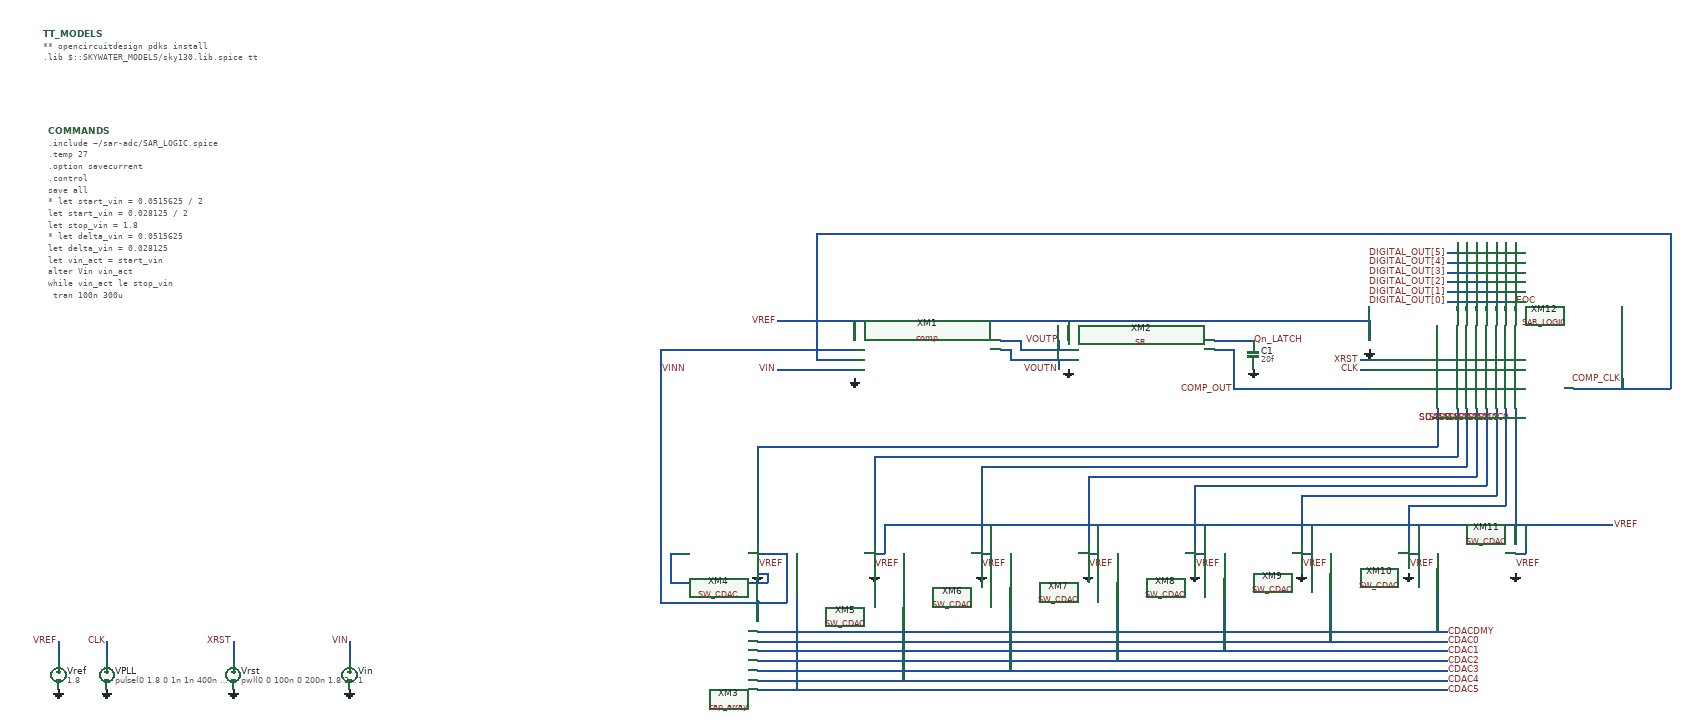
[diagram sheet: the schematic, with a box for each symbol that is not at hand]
v {xschem version=3.4.8RC file_version=1.3}
G {}
K {}
V {}
S {}
F {}
E {}
N 60 -300 60 -260 {
lab=VREF}
N 2480 -820 2760 -820 {
lab=COMP_OUT}
N 160 -300 160 -260 {
lab=CLK}
N 2740 -860 2760 -860 {
lab=CLK}
N 2740 -880 2760 -880 {
lab=XRST}
N 420 -300 420 -260 {
lab=XRST}
N 3060 -780 3060 -690 {
lab=SDAC0}
N 3050 -760 3060 -760 {
lab=SDAC0}
N 3040 -780 3040 -690 {
lab=SDAC1}
N 3030 -760 3040 -760 {
lab=SDAC1}
N 3020 -780 3020 -690 {
lab=SDAC2}
N 3010 -760 3020 -760 {
lab=SDAC2}
N 3000 -780 3000 -690 {
lab=SDAC3}
N 2990 -760 3000 -760 {
lab=SDAC3}
N 2980 -780 2980 -690 {
lab=SDAC4}
N 2970 -760 2980 -760 {
lab=SDAC4}
N 2960 -780 2960 -690 {
lab=SDAC5}
N 2950 -760 2960 -760 {
lab=SDAC5}
N 2940 -780 2940 -690 {
lab=SDAC6}
N 2930 -760 2940 -760 {
lab=SDAC6}
N 2900 -780 2900 -700 {
lab=SC}
N 2890 -760 2900 -760 {
lab=SC}
N 3180 -820 3380 -820 {
lab=COMP_CLK}
N 3280 -840 3280 -820 {
lab=COMP_CLK}
N 2000 -920 2040 -920 {
lab=VOUTP}
N 2000 -900 2020 -900 {
lab=VOUTN}
N 1500 -320 2920 -320 {
lab=CDACDMY}
N 1500 -300 2920 -300 {
lab=CDAC0}
N 1500 -280 2920 -280 {
lab=CDAC1}
N 1500 -260 2920 -260 {
lab=CDAC2}
N 1500 -240 2920 -240 {
lab=CDAC3}
N 1500 -220 2920 -220 {
lab=CDAC4}
N 1500 -200 2920 -200 {
lab=CDAC5}
N 1740 -680 2940 -680 {
lab=SDAC6}
N 1740 -680 1740 -500 {
lab=SDAC6}
N 1960 -660 1960 -500 {
lab=SDAC5}
N 1960 -660 2960 -660 {
lab=SDAC5}
N 2180 -640 2980 -640 {
lab=SDAC4}
N 2180 -640 2180 -500 {
lab=SDAC4}
N 2400 -620 2400 -500 {
lab=SDAC3}
N 2400 -620 3000 -620 {
lab=SDAC3}
N 2620 -600 3020 -600 {
lab=SDAC2}
N 2620 -600 2620 -500 {
lab=SDAC2}
N 2840 -580 2840 -500 {
lab=SDAC1}
N 3060 -690 3060 -500 {
lab=SDAC0}
N 1500 -700 2900 -700 {
lab=SC}
N 1500 -700 1500 -500 {
lab=SC}
N 1320 -480 1340 -480 {
lab=GND}
N 1320 -480 1320 -420 {
lab=GND}
N 1320 -420 1520 -420 {
lab=GND}
N 1520 -440 1520 -420 {
lab=GND}
N 1500 -440 1520 -440 {
lab=GND}
N 1500 -380 1500 -340 {
lab=VINN}
N 1300 -380 1500 -380 {
lab=VINN}
N 1300 -900 1300 -380 {
lab=VINN}
N 1300 -900 1700 -900 {
lab=VINN}
N 1500 -480 1560 -480 {
lab=VINN}
N 1560 -480 1560 -380 {
lab=VINN}
N 1500 -380 1560 -380 {
lab=VINN}
N 2840 -580 3040 -580 {
lab=SDAC1}
N 1620 -880 1700 -880 {
lab=COMP_CLK}
N 1620 -1140 1620 -880 {
lab=COMP_CLK}
N 1620 -1140 3380 -1140 {
lab=COMP_CLK}
N 3380 -1140 3380 -820 {
lab=COMP_CLK}
N 2440 -900 2480 -900 {
lab=COMP_OUT}
N 2480 -900 2480 -820 {
lab=COMP_OUT}
N 2440 -920 2520 -920 {
lab=Qn_LATCH}
N 1760 -540 3260 -540 {
lab=VREF}
N 1740 -480 1760 -480 {
lab=VREF}
N 1760 -540 1760 -480 {
lab=VREF}
N 1960 -480 1980 -480 {
lab=VREF}
N 1980 -540 1980 -480 {
lab=VREF}
N 2180 -480 2200 -480 {
lab=VREF}
N 2200 -540 2200 -480 {
lab=VREF}
N 2400 -480 2420 -480 {
lab=VREF}
N 2420 -540 2420 -480 {
lab=VREF}
N 2620 -480 2640 -480 {
lab=VREF}
N 2640 -540 2640 -480 {
lab=VREF}
N 2840 -480 2860 -480 {
lab=VREF}
N 2860 -540 2860 -480 {
lab=VREF}
N 3060 -480 3080 -480 {
lab=VREF}
N 3080 -540 3080 -480 {
lab=VREF}
N 660 -300 660 -260 {
lab=VIN}
N 1540 -860 1700 -860 {
lab=VIN}
N 2120 -880 2120 -860 {
lab=VOUTN}
N 2120 -920 2120 -900 {
lab=VOUTP}
N 2040 -920 2040 -900 {
lab=VOUTP}
N 2940 -690 2940 -680 {
lab=SDAC6}
N 2960 -690 2960 -660 {
lab=SDAC5}
N 2980 -690 2980 -640 {
lab=SDAC4}
N 3000 -690 3000 -620 {
lab=SDAC3}
N 3020 -690 3020 -600 {
lab=SDAC2}
N 3040 -690 3040 -580 {
lab=SDAC1}
N 2020 -480 2020 -240 {
lab=CDAC3}
N 1800 -480 1800 -220 {
lab=CDAC4}
N 1580 -480 1580 -200 {
lab=CDAC5}
N 2940 -1120 2940 -980 {
lab=DIGITAL_OUT[5]}
N 2920 -1100 2940 -1100 {
lab=DIGITAL_OUT[5]}
N 2920 -1080 2960 -1080 {
lab=DIGITAL_OUT[4]}
N 2920 -1060 2980 -1060 {
lab=DIGITAL_OUT[3]}
N 2920 -1040 3000 -1040 {
lab=DIGITAL_OUT[2]}
N 2920 -1020 3020 -1020 {
lab=DIGITAL_OUT[1]}
N 2920 -1000 3040 -1000 {
lab=DIGITAL_OUT[0]}
N 2960 -1120 2960 -980 {
lab=DIGITAL_OUT[4]}
N 2980 -1120 2980 -980 {
lab=DIGITAL_OUT[3]}
N 3000 -1120 3000 -980 {
lab=DIGITAL_OUT[2]}
N 3020 -1120 3020 -980 {
lab=DIGITAL_OUT[1]}
N 3040 -1120 3040 -980 {
lab=DIGITAL_OUT[0]}
N 3060 -1120 3060 -980 {
lab=EOC}
N 2020 -900 2020 -880 {
lab=VOUTN}
N 2020 -880 2140 -880 {
lab=VOUTN}
N 2040 -900 2140 -900 {
lab=VOUTP}
N 2240 -480 2240 -260 {lab=CDAC2}
N 2460 -480 2460 -280 {lab=CDAC1}
N 2680 -480 2680 -300 {lab=CDAC0}
N 2900 -480 2900 -320 {lab=CDACDMY}
N 1540 -960 2760 -960 {lab=VREF}
N 2760 -960 2760 -920 {lab=VREF}
N 2140 -960 2140 -920 {lab=VREF}
N 1700 -960 1700 -920 {lab=VREF}
C {devices/vsource.sym} 60 -230 0 0 {name=Vref value=1.8 savecurrent=false}
C {devices/gnd.sym} 160 -200 0 0 {name=l2 lab=GND}
C {devices/gnd.sym} 60 -200 0 0 {name=l3 lab=GND}
C {devices/simulator_commands_shown.sym} 40 -1350 0 0 {name=COMMANDS
simulator=ngspice
only_toplevel=false 
value=".include ~/sar-adc/SAR_LOGIC.spice
.temp 27
.option savecurrent
.control
save all

* let start_vin = 0.0515625 / 2 
let start_vin = 0.028125 / 2 
let stop_vin = 1.8
* let delta_vin = 0.0515625
let delta_vin = 0.028125
let vin_act = start_vin
alter Vin vin_act

while vin_act le stop_vin
	tran 100n 300u
	write sar_adc_tran.raw
	meas tran vin FIND v(VIN) WHEN v(EOC)=0.9 FALL=LAST
	meas tran vout5 FIND v(DIGITAL_OUT[5]) WHEN v(EOC)=0.9 FALL=LAST
	meas tran vout4 FIND v(DIGITAL_OUT[4]) WHEN v(EOC)=0.9 FALL=LAST
	meas tran vout3 FIND v(DIGITAL_OUT[3]) WHEN v(EOC)=0.9 FALL=LAST
	meas tran vout2 FIND v(DIGITAL_OUT[2]) WHEN v(EOC)=0.9 FALL=LAST
	meas tran vout1 FIND v(DIGITAL_OUT[1]) WHEN v(EOC)=0.9 FALL=LAST
	meas tran vout0 FIND v(DIGITAL_OUT[0]) WHEN v(EOC)=0.9 FALL=LAST
	print vin >> tran_sar_adc_out_typ.txt
	print vout5 >> tran_sar_adc_out_typ.txt
	print vout4 >> tran_sar_adc_out_typ.txt
	print vout3 >> tran_sar_adc_out_typ.txt
	print vout2 >> tran_sar_adc_out_typ.txt
	print vout1 >> tran_sar_adc_out_typ.txt
	print vout0 >> tran_sar_adc_out_typ.txt
	let vin_act = vin_act + delta_vin
	alter Vin vin_act
end

.endc
"}
C {devices/lab_pin.sym} 160 -300 0 0 {name=p2 sig_type=std_logic lab=CLK}
C {devices/lab_pin.sym} 2740 -860 0 0 {name=p5 sig_type=std_logic lab=CLK}
C {devices/lab_pin.sym} 2740 -880 0 0 {name=p7 sig_type=std_logic lab=XRST}
C {devices/lab_pin.sym} 420 -300 0 0 {name=p9 sig_type=std_logic lab=XRST}
C {devices/gnd.sym} 420 -200 0 0 {name=l1 lab=GND}
C {devices/lab_pin.sym} 3050 -760 3 0 {name=p10 sig_type=std_logic lab=SDAC0}
C {devices/lab_pin.sym} 3030 -760 3 0 {name=p11 sig_type=std_logic lab=SDAC1}
C {devices/lab_pin.sym} 3010 -760 3 0 {name=p12 sig_type=std_logic lab=SDAC2}
C {devices/lab_pin.sym} 2990 -760 3 0 {name=p13 sig_type=std_logic lab=SDAC3}
C {devices/lab_pin.sym} 2970 -760 3 0 {name=p14 sig_type=std_logic lab=SDAC4}
C {devices/lab_pin.sym} 2950 -760 3 0 {name=p15 sig_type=std_logic lab=SDAC5}
C {devices/lab_pin.sym} 2930 -760 3 0 {name=p16 sig_type=std_logic lab=SDAC6}
C {devices/lab_pin.sym} 2890 -760 3 0 {name=p19 sig_type=std_logic lab=SC}
C {devices/lab_pin.sym} 3280 -840 0 0 {name=p20 sig_type=std_logic lab=COMP_CLK}
C {devices/gnd.sym} 1500 -440 0 1 {name=l4 lab=GND}
C {devices/gnd.sym} 1740 -440 0 1 {name=l5 lab=GND}
C {devices/gnd.sym} 1960 -440 0 1 {name=l6 lab=GND}
C {devices/gnd.sym} 2180 -440 0 1 {name=l7 lab=GND}
C {devices/gnd.sym} 2400 -440 0 1 {name=l8 lab=GND}
C {devices/gnd.sym} 2620 -440 0 1 {name=l9 lab=GND}
C {devices/gnd.sym} 2840 -440 0 1 {name=l10 lab=GND}
C {devices/gnd.sym} 3060 -440 0 1 {name=l11 lab=GND}
C {devices/gnd.sym} 2760 -900 0 1 {name=l16 lab=GND}
C {devices/gnd.sym} 1700 -840 0 1 {name=l18 lab=GND}
C {devices/gnd.sym} 2140 -860 0 1 {name=l19 lab=GND}
C {devices/gnd.sym} 2520 -860 0 1 {name=l20 lab=GND}
C {devices/lab_pin.sym} 660 -300 2 1 {name=p25 sig_type=std_logic lab=VIN}
C {devices/gnd.sym} 660 -200 0 0 {name=l22 lab=GND}
C {devices/vsource.sym} 660 -230 0 0 {name=Vin value=1 savecurrent=false}
C {devices/lab_pin.sym} 1540 -860 0 0 {name=p26 sig_type=std_logic lab=VIN}
C {devices/lab_pin.sym} 2120 -860 0 0 {name=p27 sig_type=std_logic lab=VOUTN}
C {devices/lab_pin.sym} 2120 -920 2 1 {name=p28 sig_type=std_logic lab=VOUTP}
C {devices/lab_pin.sym} 2920 -260 0 1 {name=p29 sig_type=std_logic lab=CDAC2}
C {devices/lab_pin.sym} 2920 -280 0 1 {name=p30 sig_type=std_logic lab=CDAC1}
C {devices/lab_pin.sym} 2920 -300 0 1 {name=p31 sig_type=std_logic lab=CDAC0}
C {devices/lab_pin.sym} 2920 -320 0 1 {name=p32 sig_type=std_logic lab=CDACDMY}
C {devices/lab_pin.sym} 2920 -240 0 1 {name=p33 sig_type=std_logic lab=CDAC3}
C {devices/lab_pin.sym} 2920 -220 0 1 {name=p34 sig_type=std_logic lab=CDAC4}
C {devices/lab_pin.sym} 2920 -200 0 1 {name=p35 sig_type=std_logic lab=CDAC5}
C {devices/lab_pin.sym} 1300 -860 0 1 {name=p36 sig_type=std_logic lab=VINN}
C {devices/lab_pin.sym} 3260 -540 2 0 {name=p37 sig_type=std_logic lab=VREF}
C {devices/lab_pin.sym} 2520 -920 2 0 {name=p38 sig_type=std_logic lab=Qn_LATCH}
C {devices/lab_pin.sym} 2480 -820 0 0 {name=p39 sig_type=std_logic lab=COMP_OUT}
C {devices/lab_pin.sym} 2920 -1100 0 0 {name=p18 sig_type=std_logic lab=DIGITAL_OUT[5]}
C {devices/lab_pin.sym} 2920 -1080 0 0 {name=p21 sig_type=std_logic lab=DIGITAL_OUT[4]}
C {devices/lab_pin.sym} 2920 -1060 0 0 {name=p40 sig_type=std_logic lab=DIGITAL_OUT[3]}
C {devices/lab_pin.sym} 2920 -1040 0 0 {name=p41 sig_type=std_logic lab=DIGITAL_OUT[2]}
C {devices/lab_pin.sym} 2920 -1020 0 0 {name=p42 sig_type=std_logic lab=DIGITAL_OUT[1]}
C {devices/lab_pin.sym} 2920 -1000 0 0 {name=p43 sig_type=std_logic lab=DIGITAL_OUT[0]}
C {devices/lab_pin.sym} 3060 -1000 2 0 {name=p17 sig_type=std_logic lab=EOC}
C {comp.sym} 1850 -880 0 0 {name=XM1
spiceprefix=X}
C {SR.sym} 2290 -890 0 0 {name=XM2
spiceprefix=X
}
C {SAR_LOGIC.sym} 2970 -870 0 0 {name=XM12 prefix=SAR_LOGIC}
C {cap_array.sym} 1350 -270 0 0 {name=XM3
spiceprefix=X}
C {SW_CDAC.sym} 1500 -500 0 1 {name=XM4
spiceprefix=X}
C {SW_CDAC.sym} 1740 -500 0 1 {name=XM5
spiceprefix=X}
C {SW_CDAC.sym} 1960 -500 0 1 {name=XM6
spiceprefix=X}
C {SW_CDAC.sym} 2180 -500 0 1 {name=XM7
spiceprefix=X}
C {SW_CDAC.sym} 2400 -500 0 1 {name=XM8
spiceprefix=X}
C {SW_CDAC.sym} 2620 -500 0 1 {name=XM9
spiceprefix=X}
C {SW_CDAC.sym} 2840 -500 0 1 {name=XM10
spiceprefix=X}
C {SW_CDAC.sym} 3060 -500 0 1 {name=XM11
spiceprefix=X}
C {devices/code.sym} 30 -1550 0 0 {name=TT_MODELS
only_toplevel=true
format="tcleval( @value )"
value="
** opencircuitdesign pdks install
.lib $::SKYWATER_MODELS/sky130.lib.spice tt
"
spice_ignore=false}
C {devices/vsource.sym} 160 -230 0 0 {name=VPLL value="pulse(0 1.8 0 1n 1n 400n 800n)" savecurrent=false}
C {devices/vsource.sym} 420 -230 0 0 {name=Vrst value="pwl(0 0 100n 0 200n 1.8 200n 1.8)" savecurrent=false}
C {devices/lab_pin.sym} 60 -300 2 1 {name=p44 sig_type=std_logic lab=VREF}
C {devices/lab_pin.sym} 1540 -960 2 1 {name=p45 sig_type=std_logic lab=VREF}
C {devices/lab_pin.sym} 3060 -460 2 0 {name=p1 sig_type=std_logic lab=VREF}
C {devices/lab_pin.sym} 2840 -460 2 0 {name=p3 sig_type=std_logic lab=VREF}
C {devices/lab_pin.sym} 2620 -460 2 0 {name=p4 sig_type=std_logic lab=VREF}
C {devices/lab_pin.sym} 2400 -460 2 0 {name=p6 sig_type=std_logic lab=VREF}
C {devices/lab_pin.sym} 2180 -460 2 0 {name=p8 sig_type=std_logic lab=VREF}
C {devices/lab_pin.sym} 1960 -460 2 0 {name=p22 sig_type=std_logic lab=VREF}
C {devices/lab_pin.sym} 1740 -460 2 0 {name=p23 sig_type=std_logic lab=VREF}
C {devices/lab_pin.sym} 1500 -460 2 0 {name=p24 sig_type=std_logic lab=VREF}
C {devices/capa.sym} 2520 -890 0 0 {name=C1
m=1
value=20f
footprint=1206
device="ceramic capacitor"}
